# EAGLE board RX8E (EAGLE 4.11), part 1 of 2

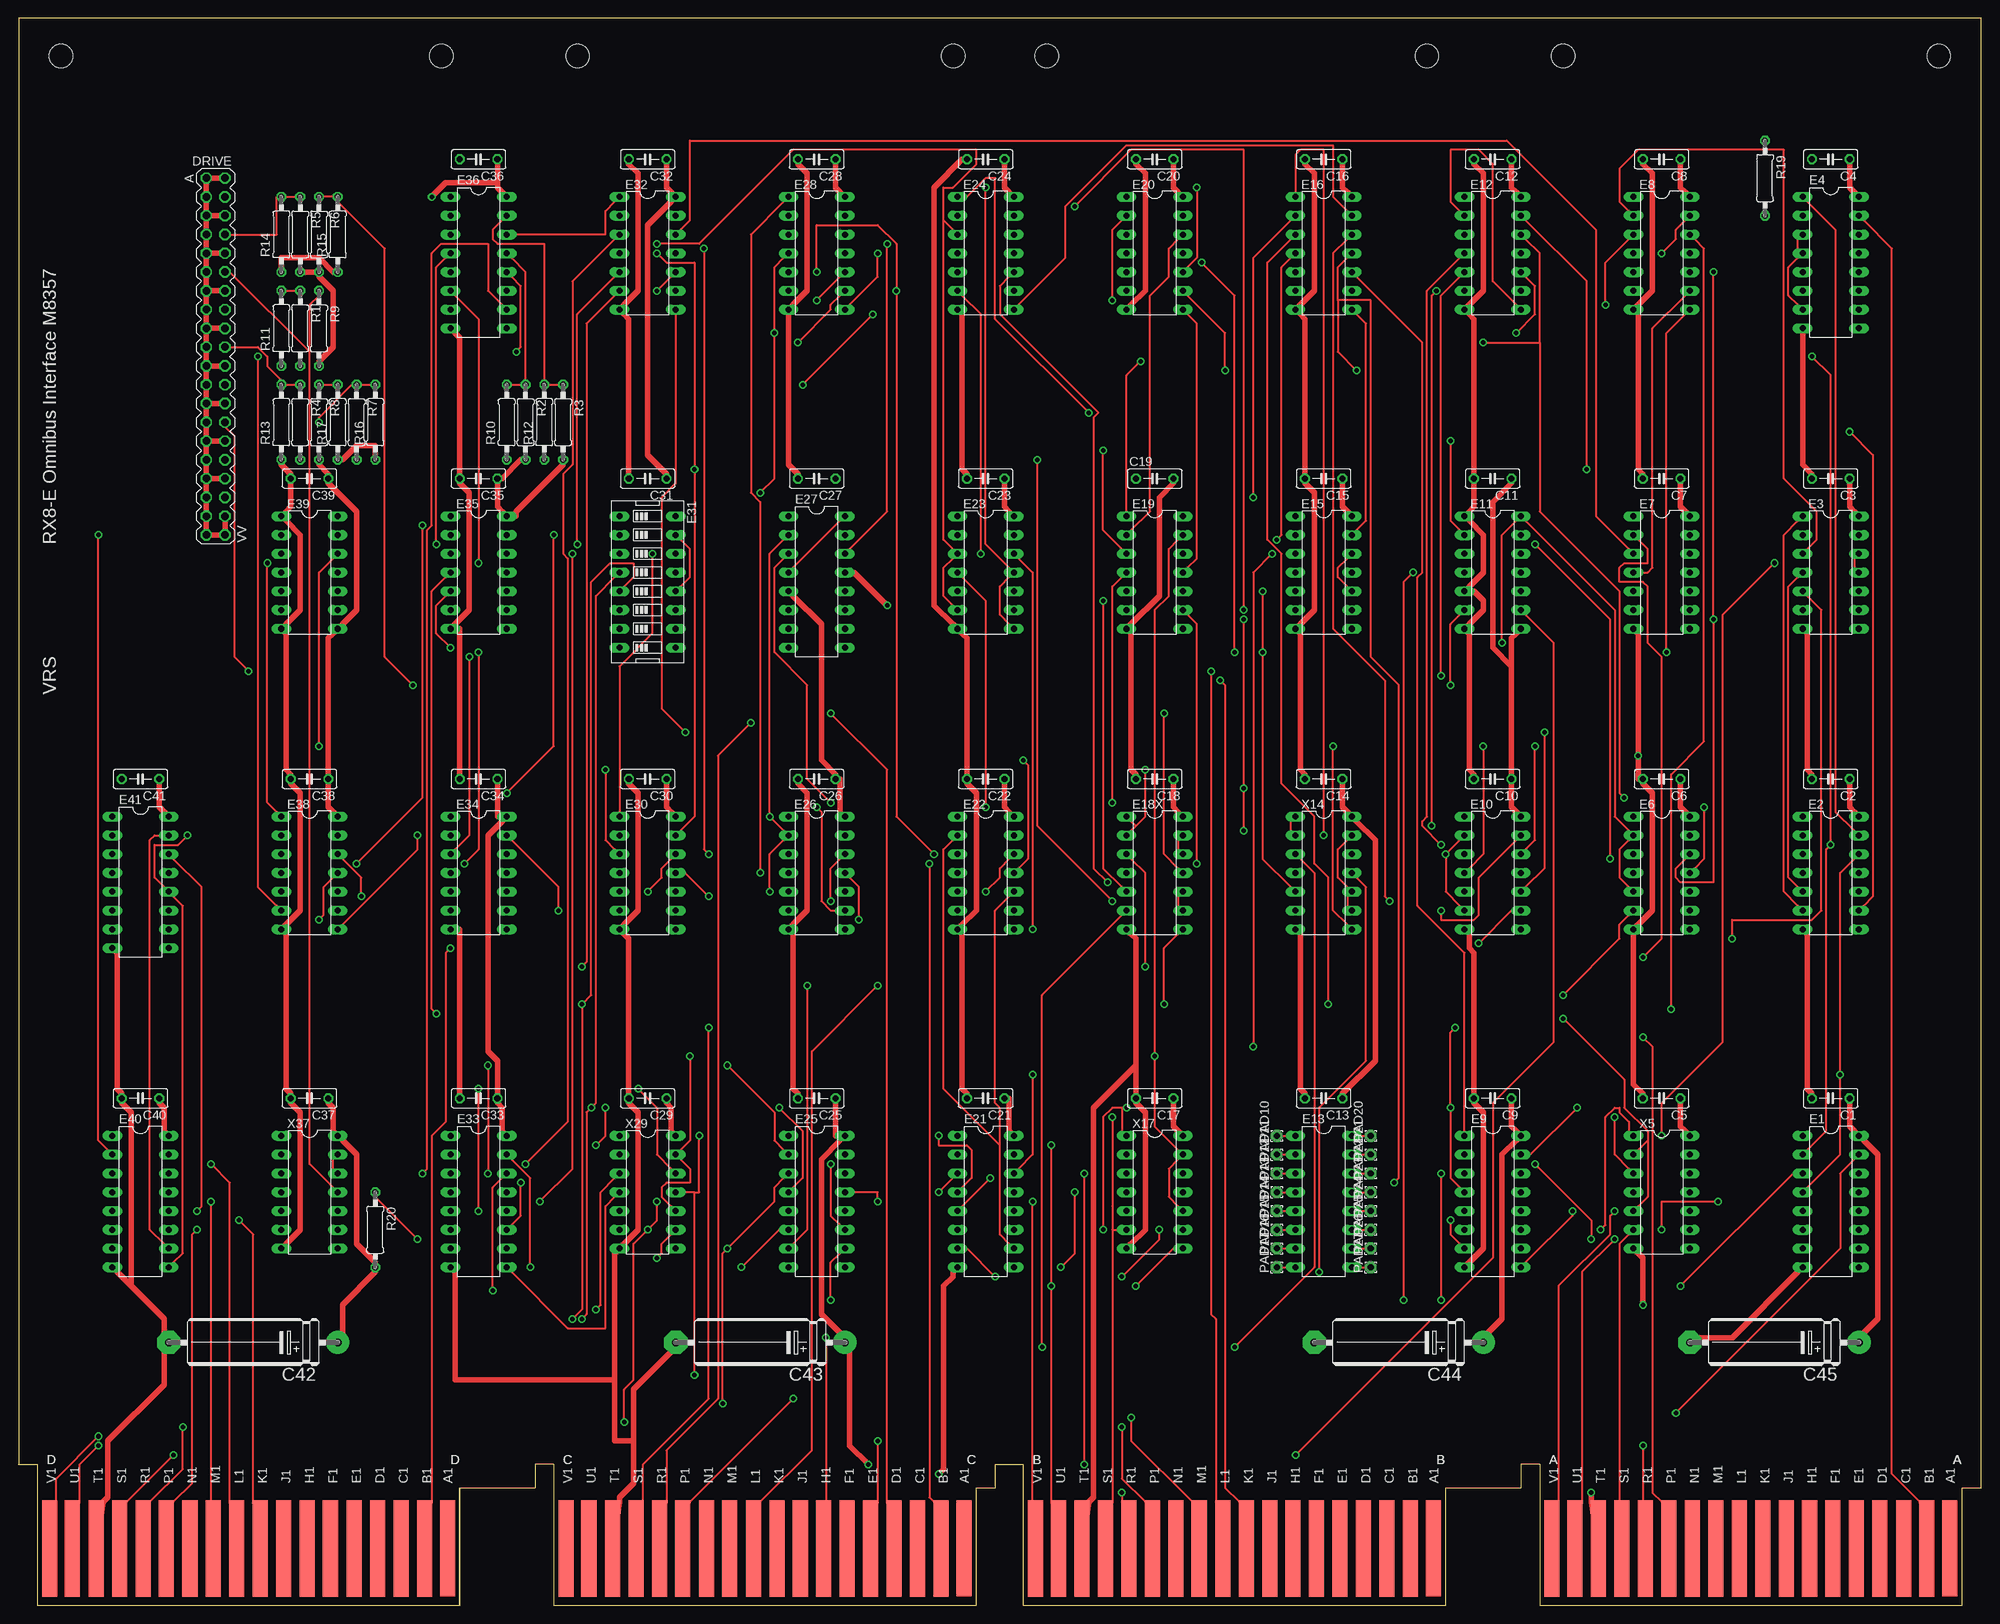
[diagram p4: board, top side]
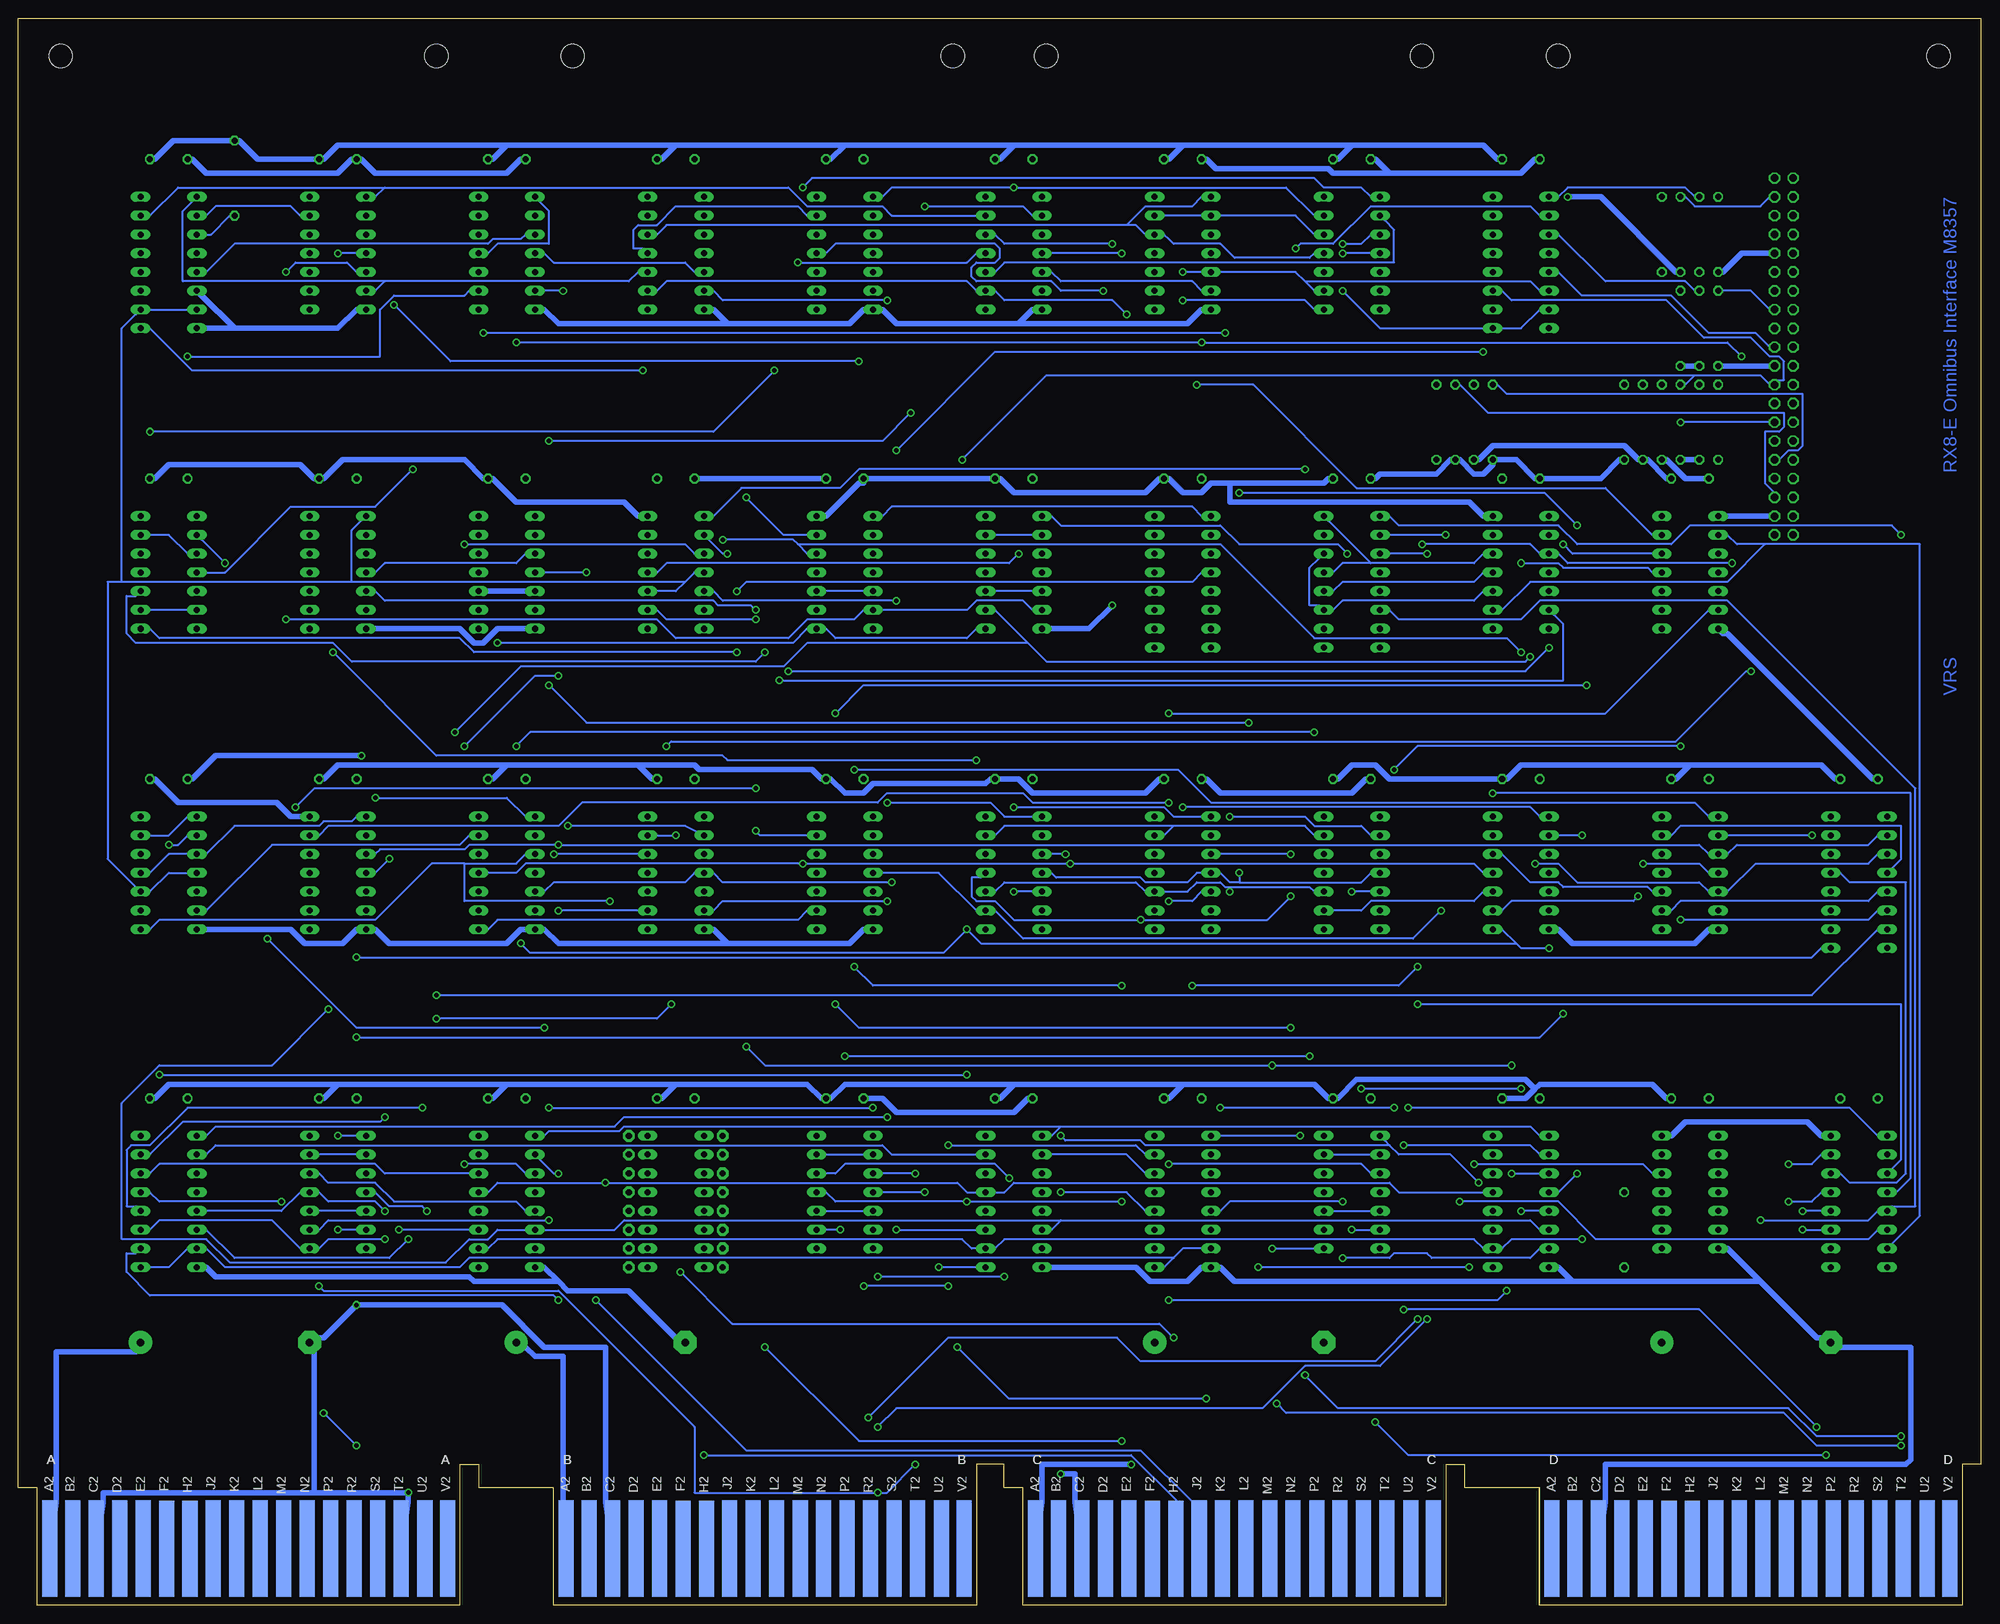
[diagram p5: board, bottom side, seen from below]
Size 265.43 x 214.63 mm. Coordinates in mm from the lower left corner, seen from the top.
Copper layers (1*16): Top 0.035mm / dielectric 1.5mm / Bottom 0.035mm
Design rules "olimex10mil": minimum track width 10mil, minimum drill 24mil, track to track 10mil, track to pad 10mil, pad to pad 10mil, via to via 10mil, smd to smd 10mil, copper to edge 25mil, drill to drill 10mil, minimum pad ring 10mil, minimum via ring 8mil, stop-mask expansion 0mil, vias tented up to drill 0mil, thermal gap 10mil
Net classes: 1 supply: width 0.762 mm

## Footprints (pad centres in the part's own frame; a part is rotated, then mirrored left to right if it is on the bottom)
C050-025X075 = drill 0.813 octagon: 1 -2.54,0; 2 2.54,0
E22-6 = drill 1.016 pad 3.15 round: + -11.43,0 | drill 1.016 pad 3.15 octagon: - 11.43,0
DEC40PIN = drill 1.016 octagon: A -24.13,-1.27; AA 3.81,-1.27; B -24.13,1.27; BB 3.81,1.27; C -21.59,-1.27; CC 6.35,-1.27; D -21.59,1.27; DD 6.35,1.27; E -19.05,-1.27; EE 8.89,-1.27; F -19.05,1.27; FF 8.89,1.27; H -16.51,-1.27; HH 11.43,-1.27; J -16.51,1.27; JJ 11.43,1.27; K -13.97,-1.27; KK 13.97,-1.27; L -13.97,1.27; LL 13.97,1.27; M -11.43,-1.27; MM 16.51,-1.27; N -11.43,1.27; NN 16.51,1.27; P -8.89,-1.27; PP 19.05,-1.27; R -8.89,1.27; RR 19.05,1.27; S -6.35,-1.27; SS 21.59,-1.27; T -6.35,1.27; TT 21.59,1.27; U -3.81,-1.27; UU 24.13,-1.27; V -3.81,1.27; VV 24.13,1.27; W -1.27,-1.27; X -1.27,1.27; Y 1.27,-1.27; Z 1.27,1.27
DIL16 = drill 0.813 long: 1 -8.89,-3.81; 2 -6.35,-3.81; 3 -3.81,-3.81; 4 -1.27,-3.81; 5 1.27,-3.81; 6 3.81,-3.81; 7 6.35,-3.81; 8 8.89,-3.81; 9 8.89,3.81; 10 6.35,3.81; 11 3.81,3.81; 12 1.27,3.81; 13 -1.27,3.81; 14 -3.81,3.81; 15 -6.35,3.81; 16 -8.89,3.81
DIL14 = drill 0.813 long: 1 -7.62,-3.81; 2 -5.08,-3.81; 3 -2.54,-3.81; 4 0,-3.81; 5 2.54,-3.81; 6 5.08,-3.81; 7 7.62,-3.81; 8 7.62,3.81; 9 5.08,3.81; 10 2.54,3.81; 11 0,3.81; 12 -2.54,3.81; 13 -5.08,3.81; 14 -7.62,3.81
EDG-08 = drill 0.813 long: 1 -8.89,-3.81; 2 -6.35,-3.81; 3 -3.81,-3.81; 4 -1.27,-3.81; 5 1.27,-3.81; 6 3.81,-3.81; 7 6.35,-3.81; 8 8.89,-3.81; 9 8.89,3.81; 10 6.35,3.81; 11 3.81,3.81; 12 1.27,3.81; 13 -1.27,3.81; 14 -3.81,3.81; 15 -6.35,3.81; 16 -8.89,3.81
1,6/0,8 = drill 0.813 pad 1.6 octagon: 1 0,0
0207/10 = drill 0.813 octagon: 1 -5.08,0; 2 5.08,0
EDGE-CON8 = smd 2.032 x 13.017: AA1 261.223,7.709; AB1 258.118,7.684; AC1 254.956,7.684; AD1 251.765,7.684; AE1 248.59,7.693; AF1 245.389,7.668; AH1 242.24,7.668; AJ1 239.09,7.668; AK1 235.915,7.668; AL1 232.74,7.693; AM1 229.54,7.693; AN1 226.39,7.693; AP1 223.19,7.668; AR1 220.04,7.668; AS1 216.865,7.693; AT1 213.69,7.693; AU1 210.49,7.693; AV1 207.404,7.668; BA1 191.373,7.709; BB1 188.268,7.684; BC1 185.106,7.684; BD1 181.915,7.684; BE1 178.74,7.693; BF1 175.539,7.668; BH1 172.39,7.668; BJ1 169.24,7.668; BK1 166.065,7.668; BL1 162.89,7.693; BM1 159.69,7.693; BN1 156.54,7.693; BP1 153.34,7.668; BR1 150.19,7.668; BS1 147.015,7.693; BT1 143.84,7.693; BU1 140.64,7.693; BV1 137.554,7.668; CA1 127.873,7.709; CB1 124.768,7.684; CC1 121.606,7.684; CD1 118.415,7.684; CE1 115.24,7.693; CF1 112.039,7.668; CH1 108.89,7.668; CJ1 105.74,7.668; CK1 102.565,7.668; CL1 99.39,7.693; CM1 96.19,7.693; CN1 93.04,7.693; CP1 89.84,7.668; CR1 86.69,7.668; CS1 83.515,7.693; CT1 80.34,7.693; CU1 77.14,7.693; CV1 74.054,7.668; DA1 58.023,7.709; DB1 54.918,7.684; DC1 51.756,7.684; DD1 48.565,7.684; DE1 45.39,7.693; DF1 42.189,7.668; DH1 39.04,7.668; DJ1 35.89,7.668; DK1 32.715,7.668; DL1 29.54,7.693; DM1 26.34,7.693; DN1 23.19,7.693; DP1 19.99,7.668; DR1 16.84,7.668; DS1 13.665,7.693; DT1 10.49,7.693; DU1 7.29,7.693; DV1 4.204,7.668 | smd 2.032 x 13.017 bottom: AA2 261.223,7.69; AB2 258.102,7.668; AC2 254.94,7.668; AD2 251.765,7.693; AE2 248.59,7.693; AF2 245.389,7.642; AH2 242.24,7.642; AJ2 239.09,7.668; AK2 235.915,7.668; AL2 232.74,7.693; AM2 229.54,7.693; AN2 226.39,7.693; AP2 223.19,7.668; AR2 220.04,7.668; AS2 216.865,7.693; AT2 213.69,7.693; AU2 210.464,7.693; AV2 207.404,7.668; BA2 191.373,7.69; BB2 188.252,7.668; BC2 185.09,7.668; BD2 181.915,7.693; BE2 178.74,7.693; BF2 175.539,7.642; BH2 172.39,7.642; BJ2 169.24,7.668; BK2 166.065,7.668; BL2 162.89,7.693; BM2 159.69,7.693; BN2 156.54,7.693; BP2 153.34,7.668; BR2 150.19,7.668; BS2 147.015,7.693; BT2 143.84,7.693; BU2 140.614,7.693; BV2 137.554,7.668; CA2 127.873,7.69; CB2 124.752,7.668; CC2 121.59,7.668; CD2 118.415,7.693; CE2 115.24,7.693; CF2 112.039,7.642; CH2 108.89,7.642; CJ2 105.74,7.668; CK2 102.565,7.668; CL2 99.39,7.693; CM2 96.19,7.693; CN2 93.04,7.693; CP2 89.84,7.668; CR2 86.69,7.668; CS2 83.515,7.693; CT2 80.34,7.693; CU2 77.114,7.693; CV2 74.054,7.668; DA2 58.023,7.69; DB2 54.902,7.668; DC2 51.74,7.668; DD2 48.565,7.693; DE2 45.39,7.693; DF2 42.189,7.642; DH2 39.04,7.642; DJ2 35.89,7.668; DK2 32.715,7.668; DL2 29.54,7.693; DM2 26.34,7.693; DN2 23.19,7.693; DP2 19.99,7.668; DR2 16.84,7.668; DS2 13.665,7.693; DT2 10.49,7.693; DU2 7.264,7.693; DV2 4.204,7.668
OMNIBUS = hole 3.175: 208.915,209.55; 259.715,209.55; 190.5,209.55; 139.065,209.55; 75.616,209.55; 126.416,209.55; 57.201,209.55; 5.766,209.55

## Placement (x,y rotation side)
C1  0.1  [C050-025X075]  245.11,68.58 180 top
C2  0.1  [C050-025X075]  245.11,111.76 180 top
C3  0.1  [C050-025X075]  245.11,152.4 180 top
C4  0.1  [C050-025X075]  245.11,195.58 180 top
C5  0.1  [C050-025X075]  222.25,68.58 180 top
C6  0.1  [C050-025X075]  222.25,111.76 180 top
C7  0.1  [C050-025X075]  222.25,152.4 180 top
C8  0.1  [C050-025X075]  222.25,195.58 180 top
C9  0.1  [C050-025X075]  199.39,68.58 180 top
C10  0.1  [C050-025X075]  199.39,111.76 180 top
C11  0.1  [C050-025X075]  199.39,152.4 180 top
C12  0.1  [C050-025X075]  199.39,195.58 180 top
C13  0.1  [C050-025X075]  176.53,68.58 180 top
C14  0.1  [C050-025X075]  176.53,111.76 180 top
C15  0.1  [C050-025X075]  176.53,152.4 180 top
C16  0.1  [C050-025X075]  176.53,195.58 180 top
C17  0.1  [C050-025X075]  153.67,68.58 180 top
C18  0.1  [C050-025X075]  153.67,111.76 180 top
C19  0.1  [C050-025X075]  153.67,152.4 0 top
C20  0.1  [C050-025X075]  153.67,195.58 180 top
C21  0.1  [C050-025X075]  130.81,68.58 180 top
C22  0.1  [C050-025X075]  130.81,111.76 180 top
C23  0.1  [C050-025X075]  130.81,152.4 180 top
C24  0.1  [C050-025X075]  130.81,195.58 180 top
C25  0.1  [C050-025X075]  107.95,68.58 180 top
C26  0.1  [C050-025X075]  107.95,111.76 180 top
C27  0.1  [C050-025X075]  107.95,152.4 180 top
C28  0.1  [C050-025X075]  107.95,195.58 180 top
C29  0.1  [C050-025X075]  85.09,68.58 180 top
C30  0.1  [C050-025X075]  85.09,111.76 180 top
C31  0.1  [C050-025X075]  85.09,152.4 180 top
C32  0.1  [C050-025X075]  85.09,195.58 180 top
C33  0.1  [C050-025X075]  62.23,68.58 180 top
C34  0.1  [C050-025X075]  62.23,111.76 180 top
C35  0.1  [C050-025X075]  62.23,152.4 180 top
C36  0.1  [C050-025X075]  62.23,195.58 180 top
C37  0.1  [C050-025X075]  39.37,68.58 180 top
C38  0.1  [C050-025X075]  39.37,111.76 180 top
C39  0.1  [C050-025X075]  39.37,152.4 180 top
C40  0.1  [C050-025X075]  16.51,68.58 180 top
C41  0.1  [C050-025X075]  16.51,111.76 180 top
C42  6.8uf  [E22-6]  31.75,35.56 180 top
C43  6.8uf  [E22-6]  100.33,35.56 180 top
C44  6.8uf  [E22-6]  186.69,35.56 180 top
C45  6.8uf  [E22-6]  237.49,35.56 180 top
DRIVE  [DEC40PIN]  26.67,168.91 270 top
E1  DS8837N  [DIL16]  245.11,54.61 270 top
E2  74LS74N  [DIL14]  245.11,99.06 270 top
E3  74LS10N  [DIL14]  245.11,139.7 270 top
E4  74161N  [DIL16]  245.11,181.61 270 top
E6  74LS02N  [DIL14]  222.25,99.06 270 top
E7  74LS74N  [DIL14]  222.25,139.7 270 top
E8  74LS04N  [DIL14]  222.25,182.88 270 top
E9  74179N  [DIL16]  199.39,54.61 270 top
E10  74LS10N  [DIL14]  199.39,99.06 270 top
E11  DS8640N  [DIL14]  199.39,139.7 270 top
E12  74LS00N  [DIL14]  199.39,182.88 270 top
E13  SPARE  [DIL16]  176.53,54.61 270 top
E15  74LS74N  [DIL14]  176.53,139.7 270 top
E16  74LS08N  [DIL14]  176.53,182.88 270 top
E18X  7438N  [DIL14]  153.67,99.06 270 top
E19  74LS02N  [DIL14]  153.67,139.7 270 top
E20  74LS27N  [DIL14]  153.67,182.88 270 top
E21  74179N  [DIL16]  130.81,54.61 270 top
E22  74LS74N  [DIL14]  130.81,99.06 270 top
E23  74LS02N  [DIL14]  130.81,139.7 270 top
E24  74LS00N  [DIL14]  130.81,182.88 270 top
E25  DS8837N  [DIL16]  107.95,54.61 270 top
E26  74LS74N  [DIL14]  107.95,99.06 270 top
E27  7476N  [DIL16]  107.95,138.43 270 top
E28  74LS20N  [DIL14]  107.95,182.88 270 top
E30  74LS74N  [DIL14]  85.09,99.06 270 top
E31  [EDG-08]  85.09,138.43 270 top
E32  74LS04N  [DIL14]  85.09,182.88 270 top
E33  74179N  [DIL16]  62.23,54.61 270 top
E34  7400N  [DIL14]  62.23,99.06 270 top
E35  SP314N  [DIL14]  62.23,139.7 270 top
E36  DS8837N  [DIL16]  62.23,181.61 270 top
E38  74LS04N  [DIL14]  39.37,99.06 270 top
E39  SP384N  [DIL14]  39.37,139.7 270 top
E40  DS8837N  [DIL16]  16.51,54.61 270 top
E41  74LS42N  [DIL16]  16.51,97.79 270 top
PAD10  [1,6/0,8]  170.18,63.5 90 top
PAD11  [1,6/0,8]  170.18,60.96 90 top
PAD12  [1,6/0,8]  170.18,58.42 90 top
PAD13  [1,6/0,8]  170.18,55.88 90 top
PAD14  [1,6/0,8]  170.18,53.34 90 top
PAD15  [1,6/0,8]  170.18,50.8 90 top
PAD16  [1,6/0,8]  170.18,48.26 90 top
PAD17  [1,6/0,8]  170.18,45.72 90 top
PAD20  [1,6/0,8]  182.88,63.5 90 top
PAD21  [1,6/0,8]  182.88,60.96 90 top
PAD22  [1,6/0,8]  182.88,58.42 90 top
PAD23  [1,6/0,8]  182.88,55.88 90 top
PAD24  [1,6/0,8]  182.88,53.34 90 top
PAD25  [1,6/0,8]  182.88,50.8 90 top
PAD26  [1,6/0,8]  182.88,48.26 90 top
PAD27  [1,6/0,8]  182.88,45.72 90 top
R1  180  [0207/10]  38.1,172.72 270 top
R2  180  [0207/10]  68.58,160.02 270 top
R3  180  [0207/10]  73.66,160.02 270 top
R4  180  [0207/10]  38.1,160.02 270 top
R5  180  [0207/10]  38.1,185.42 270 top
R6  180  [0207/10]  40.64,185.42 270 top
R7  180  [0207/10]  45.72,160.02 270 top
R8  180  [0207/10]  40.64,160.02 270 top
R9  120  [0207/10]  40.64,172.72 270 top
R10  390  [0207/10]  66.04,160.02 90 top
R11  390  [0207/10]  35.56,172.72 90 top
R12  390  [0207/10]  71.12,160.02 90 top
R13  390  [0207/10]  35.56,160.02 90 top
R14  390  [0207/10]  35.56,185.42 90 top
R15  390  [0207/10]  43.18,185.42 90 top
R16  390  [0207/10]  48.26,160.02 90 top
R17  390  [0207/10]  43.18,160.02 90 top
R19  10K  [0207/10]  236.22,193.04 270 top
R20  10K  [0207/10]  48.26,50.8 270 top
U$2  [EDGE-CON8]  0,0 0 top
U$5  OUTLINE-OMNIBUS  [OMNIBUS]  0,0 0 top
X5  7438N  [DIL14]  222.25,55.88 270 top
X14  7438N  [DIL14]  176.53,99.06 270 top
X17  7438N  [DIL14]  153.67,55.88 270 top
X29  7438N  [DIL14]  85.09,55.88 270 top
X37  7438N  [DIL14]  39.37,55.88 270 top

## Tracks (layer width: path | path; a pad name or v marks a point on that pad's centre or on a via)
8/12  (via drill 0.61)
  Top 0.254: E2.5 240.66,97.16 239.4,98.43 239.4,137.8 240.66,139.07 E3.4 | v212.09,153.67 212.09,179.07 203.84,187.33 E12.13
  Bottom 0.254: v212.09,153.67 217.17,148.59 228.6,148.59 237.49,139.7 240.03,139.7 E3.4
8/12\  (via drill 0.61)
  Top 0.254: E3.1 240.66,146.69 238.76,144.78 238.76,96.52 240.66,94.62 E2.6 | X14.9 179.71,94.62 179.71,95.89 X14.10 179.71,97.16 178.44,98.43 178.44,102.24 179.71,103.51 X14.13 | v176.53,104.14 176.53,196.85 173.35,196.85 172.72,196.22 172.72,191.14 E16.1 | v192.41,93.98 192.41,92.71 196.85,92.71 197.49,93.35 197.49,98.43 202.56,103.51 E10.13
  Bottom 0.254: E2.6 240.03,93.98 231.14,102.87 205.74,102.87 204.47,104.14 E10.13 | v176.53,104.14 179.07,104.14 X14.13 | v192.41,93.98 181.61,93.98 X14.9
A-
  Top 0.254: E4.3 240.66,184.79 240.66,183.52 E4.4 240.66,182.25 239.4,180.98 239.4,177.17 240.66,175.9 E4.7 | E15.12 179.71,141.61 178.44,140.34 178.44,139.07 179.71,137.8 E15.10
  Bottom 0.254: E4.7 242.57,175.26 247.65,175.26 E4.10 249.56,174.63 251.46,172.72 251.46,138.43 | R19.2 236.85,187.96 239.4,185.42 240.03,185.42 E4.3 | E2.4 242.57,99.06 245.11,99.06 247.65,96.52 E2.10 249.56,97.16 253.37,100.97 253.37,138.43 251.46,138.43 | 175.26,138.43 176.53,137.16 179.07,137.16 E15.10 | 175.26,138.43 173.99,139.7 E15.4 | 220.34,138.43 220.34,145.42 219.07,146.69 E7.1 | 175.26,138.43 220.34,138.43 | 220.34,138.43 251.46,138.43
B-  (via drill 0.61)
  Top 0.254: E27.2 103.5,144.15 101.6,142.24 v101.6,106.68 103.5,104.78 E26.2 103.5,103.51 101.6,101.6 v101.6,96.52 | v53.98,49.53 48.26,55.25 R20.1 | 132.72,62.23 132.72,67.31 132.08,67.95 132.08,93.98 133.99,95.89 E22.10 | 132.72,62.23 132.72,50.17 133.99,48.9 E21.10 | 132.72,62.23 125.09,69.85 125.09,102.24 126.36,103.51 E22.2
  Bottom 0.254: v101.6,106.68 91.44,106.68 90.17,105.41 83.82,105.41 82.55,104.14 E30.2 | v53.98,49.53 63.5,49.53 64.77,48.26 E33.10 67.31,48.26 68.58,49.53 132.08,49.53 133.35,48.26 E21.10 135.89,48.26 136.53,48.26 137.79,49.53 200.66,49.53 201.93,48.26 E9.10 | 101.6,97.16 102.23,97.16 102.87,97.79 106.05,97.79 107.31,96.52 110.49,96.52 E26.10 113.03,96.52 114.3,97.79 132.08,97.79 133.35,96.52 E22.10 | 101.6,97.16 90.81,97.16 90.17,96.52 E30.10 | 101.6,97.16 v101.6,96.52
B_MAINT  (via drill 0.61)
  Top 0.254: v86.36,177.8 88.27,179.71 E32.10
  Bottom 0.254: E36.7 59.69,175.26 62.23,172.72 64.77,172.72 E36.9 67.31,172.72 81.28,172.72 v86.36,177.8
BINIT\  (via drill 0.61)
  Top 0.254: v86.36,182.88 87.63,181.61 91.44,181.61 v91.44,153.67 91.44,106.68 89.53,104.78 E30.13
  Bottom 0.254: 109.22,105.41 91.44,105.41 90.17,104.14 E30.13 | 109.22,105.41 110.49,104.14 E26.13 | 109.22,105.41 132.08,105.41 133.35,104.14 E22.13 | v86.36,182.88 82.55,182.88 E32.4 | v91.44,153.67 151.76,153.67 154.31,151.13 167.64,151.13 171.45,147.32 E15.1
BTP3
  Top 0.254: E7.3 217.81,142.88 213.36,147.32 213.36,186.06 201.29,198.12 90.81,198.12 90.81,187.33 89.53,186.06 E32.12
  Bottom 0.254: E32.12 90.17,185.42 92.71,187.96 102.87,187.96 E28.2 105.41,187.96 110.49,187.96 E28.13
BTP4  (via drill 0.61)
  Top 0.254: v93.34,95.89 90.17,99.06 E30.11 | v113.67,92.71 113.67,97.16 112.39,98.43 E26.11 | v222.88,128.91 222.88,172.09 225.43,174.63 E8.8 | v135.89,114.3 136.53,113.67 136.53,100.97 135.25,99.7 E22.11
  Bottom 0.254: v93.34,95.89 96.52,92.71 v113.67,92.71 130.81,92.71 133.35,95.25 135.89,95.25 136.53,95.89 136.53,98.43 135.25,98.43 E22.11 | v222.88,128.91 208.91,114.94 170.18,114.94 169.54,114.3 v135.89,114.3
C0\  (via drill 0.61)
  Top 0.254: v164.47,34.93 175.26,45.72 175.26,99.06 173.35,100.97 X14.3 | v116.2,22.23 116.2,13.97 U$2.CE1
  Bottom 0.254: v164.47,34.93 151.76,22.23 v116.2,22.23
C1\  (via drill 0.61)
  Top 0.254: v175.9,45.09 175.9,67.31 182.25,73.66 182.25,97.16 180.97,98.43 X14.11 | v109.22,36.2 109.22,13.97 U$2.CH1
  Bottom 0.254: v175.9,45.09 168.91,38.1 111.12,38.1 v109.22,36.2
CLK_BUF\  (via drill 0.61)
  Top 0.254: v223.52,80.65 223.52,112.4 227.97,116.84 227.97,183.52 226.69,184.79 E8.12
  Bottom 0.254: 124.46,52.07 60.96,52.07 59.69,50.8 E33.6 | 124.46,52.07 125.73,50.8 E21.6 | 124.46,52.07 183.51,52.07 184.78,50.8 194.31,50.8 E9.6 196.85,50.8 200.66,50.8 201.93,49.53 204.47,49.53 207.65,46.36 236.85,46.36 240.03,49.53 251.46,49.53 251.46,67.95 246.38,73.03 231.14,73.03 v223.52,80.65
CLK_PARITY\  (via drill 0.61)
  Top 0.254: v214.63,175.9 214.63,181.61 217.81,184.79 E8.3 | v151.76,168.28 149.86,166.37 149.86,147.96 E19.1
  Bottom 0.254: E27.1 105.41,147.32 106.68,148.59 147.32,148.59 148.59,147.32 E19.1 | v214.63,175.9 207.01,168.28 v151.76,168.28
DATA0
  Bottom 0.254: E9.14 204.47,58.42 215.9,58.42 217.17,59.69 246.38,59.69 247.65,58.42 E1.14
DATA0\  (via drill 0.61)
  Top 0.254: v215.9,66.04 215.9,60.96 217.81,59.06 X5.3 | v219.71,21.59 219.71,13.97 U$2.AR1 | v224.16,26.04 246.38,48.26 246.38,58.42 248.28,60.33 E1.15
  Bottom 0.254: v215.9,66.04 216.53,65.41 243.21,65.41 247.65,60.96 E1.15 | v224.16,26.04 v219.71,21.59
DATA1  (via drill 0.61)
  Top 0.254: v210.82,67.31 204.47,60.96 E9.15
  Bottom 0.254: v210.82,67.31 242.57,67.31 247.65,62.23 250.19,62.23 250.82,61.6 250.82,53.98 249.56,53.98 E1.12
DATA1\  (via drill 0.61)
  Top 0.254: X5.6 217.81,50.17 216.53,48.9 216.53,13.97 U$2.AS1 | v229.87,54.61 222.25,54.61 v222.25,50.8
  Bottom 0.254: v229.87,54.61 246.38,54.61 247.65,55.88 E1.13 | v222.25,50.8 219.71,50.8 X5.6
DATA2  (via drill 0.61)
  Top 0.254: v192.41,58.42 v192.41,41.28
  Bottom 0.254: v192.41,58.42 193.04,58.42 194.94,60.33 E9.2 | v192.41,41.28 193.04,41.91 247.65,41.91 250.82,45.09 250.82,47.63 249.56,47.63 E1.10
DATA2\  (via drill 0.61)
  Top 0.254: v215.9,49.53 211.46,45.09 211.46,13.97 U$2.AU1
  Bottom 0.254: E1.11 247.65,50.8 246.38,52.07 231.14,52.07 227.33,48.26 X5.8 224.79,48.26 223.52,49.53 v215.9,49.53
DATA3  (via drill 0.61)
  Top 0.254: v205.1,59.69 212.72,52.07 v212.72,49.53
  Bottom 0.254: v205.1,59.69 198.12,59.69 196.85,58.42 E9.3 | v212.72,49.53 215.26,46.99 236.22,46.99 240.03,50.8 E1.6
DATA3\  (via drill 0.61)
  Top 0.254: v215.9,53.34 215.26,52.71 215.26,50.17 208.28,43.18 208.28,13.97 U$2.AV1
  Bottom 0.254: E1.5 240.03,53.34 229.87,53.34 227.33,55.88 X5.11 224.79,55.88 223.52,54.61 217.17,54.61 v215.9,53.34
DATA4  (via drill 0.61)
  Top 0.254: E1.4 241.94,56.52 246.38,60.96 v246.38,71.76 246.38,99.06 248.28,100.97 E2.12 | v137.16,71.76 137.16,60.96 135.25,59.06 E21.14
  Bottom 0.254: v246.38,71.76 v137.16,71.76
DATA4\  (via drill 0.61)
  Top 0.254: v144.15,19.05 v144.15,58.42 | v149.22,15.24 149.22,13.97 U$2.BR1 | v224.79,43.18 240.03,58.42 E1.3
  Bottom 0.254: v144.15,58.42 148.59,58.42 X17.3 | v144.15,19.05 147.96,15.24 v149.22,15.24 173.99,15.24 173.99,24.13 192.41,42.55 224.16,42.55 v224.79,43.18
DATA5  (via drill 0.61)
  Top 0.254: E1.2 241.94,61.6 244.47,64.14 244.47,102.24 v245.11,102.87 245.11,166.37 v242.57,168.91
  Bottom 0.254: E21.15 135.89,60.96 147.32,60.96 148.59,62.23 238.76,62.23 240.03,60.96 E1.2 | v245.11,102.87 243.84,102.87 242.57,104.14 E2.2 | v242.57,168.91 216.53,168.91 216.53,175.26 214.63,177.17 205.1,177.17 204.47,177.8 E12.9
DATA5\  (via drill 0.61)
  Top 0.254: 147.96,50.8 147.96,53.98 v147.96,66.04 | 147.96,50.8 147.96,13.97 U$2.BS1 | 147.96,50.8 148.59,50.8 X17.6
  Bottom 0.254: v147.96,66.04 183.51,66.04 184.78,64.77 238.76,64.77 240.03,63.5 E1.1
DATA6
  Bottom 0.254: E25.14 113.03,58.42 115.57,60.96 125.73,60.96 E21.2
DATA6\  (via drill 0.61)
  Top 0.254: v139.7,62.23 v139.7,43.18 139.7,13.97 U$2.BU1 | v151.13,43.18 156.21,48.26 X17.8
  Bottom 0.254: v139.7,62.23 114.3,62.23 113.03,60.96 E25.15 | v139.7,43.18 v151.13,43.18
DATA7  (via drill 0.61)
  Top 0.254: v124.46,55.88 126.36,57.79 E21.3
  Bottom 0.254: v124.46,55.88 115.57,55.88 113.03,53.34 E25.12
DATA7\  (via drill 0.61)
  Top 0.254: v116.2,54.61 116.2,55.88 113.03,55.88 E25.13 | v137.16,54.61 137.16,13.97 U$2.BV1
  Bottom 0.254: v116.2,54.61 v137.16,54.61 154.94,54.61 156.21,55.88 X17.11
DATA8  (via drill 0.61)
  Top 0.254: v64.14,42.55 64.14,56.52 65.41,57.79 E33.14 | v109.86,41.28 109.86,46.36 111.12,47.63 E25.10
  Bottom 0.254: v64.14,42.55 65.41,41.28 v109.86,41.28
DATA8\  (via drill 0.61)
  Top 0.254: v109.86,59.69 109.86,52.71 111.12,51.44 E25.11 | v22.23,24.13 22.23,18.42 17.78,13.97 U$2.DR1 | v78.11,40.01 78.74,40.64 78.74,55.88 80.64,57.79 X29.3
  Bottom 0.254: v109.86,59.69 83.82,59.69 82.55,58.42 X29.3 | v22.23,24.13 38.1,40.01 v78.11,40.01
DATA9  (via drill 0.61)
  Top 0.254: v69.22,45.72 69.22,57.79 66.67,60.33 E33.15 | v97.79,45.72 102.87,50.8 E25.6
  Bottom 0.254: v69.22,45.72 v97.79,45.72
DATA9\  (via drill 0.61)
  Top 0.254: v86.36,54.61 86.36,52.07 v85.09,50.8 83.19,48.9 83.19,30.48 81.92,29.21 v81.92,24.77 | v20.95,20.32 14.61,13.97 U$2.DS1
  Bottom 0.254: v85.09,50.8 82.55,50.8 X29.6 | v86.36,54.61 101.6,54.61 102.87,53.34 E25.5 | v81.92,24.77 77.47,20.32 v20.95,20.32
DATA10  (via drill 0.61)
  Top 0.254: v78.11,62.23 79.38,63.5 v79.38,67.31 | v102.87,67.31 106.05,64.14 106.05,57.79 104.78,56.52 E25.4
  Bottom 0.254: v78.11,62.23 60.96,62.23 59.69,60.96 E33.2 | v79.38,67.31 v102.87,67.31
DATA10\  (via drill 0.61)
  Top 0.254: E25.3 103.5,57.79 102.23,56.52 102.23,54.61 v95.89,48.26 95.25,47.63 v95.25,27.31 | v10.79,21.59 8.26,19.05 8.26,13.97 U$2.DU1
  Bottom 0.254: v95.89,48.26 90.17,48.26 X29.8 | v95.25,27.31 93.98,26.04 26.67,26.04 22.23,21.59 v10.79,21.59
DATA11  (via drill 0.61)
  Top 0.254: v63.5,73.03 v63.5,58.42 | v95.89,73.03 102.23,66.68 102.23,62.87 103.5,61.6 E25.2 | v169.54,142.24 167,139.7 v167,75.57
  Bottom 0.254: v63.5,58.42 59.69,58.42 E33.3 | v63.5,73.03 v95.89,73.03 164.47,73.03 v167,75.57 | v169.54,142.24 170.18,142.24 172.09,144.15 E15.2
DATA11\  (via drill 0.61)
  Top 0.254: 91.44,55.88 92.08,55.88 v92.08,63.5 | 91.44,55.88 90.17,55.88 X29.11 | v91.44,31.12 91.44,55.88 | v10.79,22.86 5.08,17.15 5.08,13.97 U$2.DV1
  Bottom 0.254: v92.08,63.5 102.87,63.5 E25.1 | v91.44,31.12 87,26.67 26.04,26.67 22.23,22.86 v10.79,22.86
DONE  (via drill 0.61)
  Top 0.254: v62.23,140.97 62.23,173.99 59.05,177.17 E36.6 | v123.83,101.6 118.75,106.68 v118.75,177.8 118.75,184.15 116.2,186.69 107.95,186.69 v107.95,180.34
  Bottom 0.254: v62.23,140.97 57.15,140.97 56.52,140.34 45.09,140.34 44.45,139.7 E39.11 | 91.44,179.07 92.71,180.34 102.87,180.34 E28.5 105.41,180.34 v107.95,180.34 | 91.44,179.07 90.17,177.8 E32.9 | 91.44,179.07 60.96,179.07 59.69,177.8 E36.6 | v123.83,101.6 125.73,101.6 E22.3 | v118.75,177.8 124.46,177.8 125.73,179.07 135.89,179.07 136.53,179.71 136.53,180.98 135.89,181.61 133.35,181.61 132.72,182.25 132.72,183.52 133.35,184.15 154.94,184.15 156.21,182.88 E20.11
DONE\  (via drill 0.61)
  Top 0.254: v107.95,176.53 111.12,179.71 E28.10 | v198.12,116.21 198.12,101.6 196.22,99.7 E10.4 | v90.17,118.11 87,121.29 87,149.86 88.9,151.77 88.9,174.63 E32.8
  Bottom 0.254: v107.95,176.53 91.44,176.53 90.17,175.26 E32.8 | v198.12,116.21 196.22,118.11 v90.17,118.11
DONE_SKIP\  (via drill 0.61)
  Top 0.254: v159.38,100.33 159.38,132.72 158.12,133.99 E19.9 | v123.19,100.33 123.19,14.61 123.83,13.97 U$2.CB1
  Bottom 0.254: E34.11 67.31,99.06 68.58,100.33 v123.19,100.33 v159.38,100.33 196.85,100.33 198.12,99.06 201.93,99.06 E10.11
ENB_BUF_LD\  (via drill 0.61)
  Top 0.254: v180.97,167.01 178.44,169.55 178.44,176.53 | 178.44,176.53 178.44,180.98 179.71,182.25 E16.11 | 178.44,176.53 182.88,176.53 182.88,128.27 186.69,124.46 186.69,57.79 v186.06,57.15
  Bottom 0.254: E20.13 158.75,187.96 160.02,189.23 176.53,189.23 179.07,186.69 181.61,186.69 182.25,186.06 182.25,183.52 180.97,183.52 E16.11 | v180.97,167.01 241.94,167.01 247.65,172.72 E4.9 | E33.13 67.31,55.88 78.74,55.88 80.01,57.15 130.81,57.15 132.08,55.88 133.35,55.88 E21.13 135.89,55.88 137.16,55.88 138.43,57.15 v186.06,57.15 200.66,57.15 201.93,55.88 E9.13
ERR_SKIP\  (via drill 0.61)
  Top 0.254: v60.96,128.27 60.96,104.14 59.05,102.24 E34.3 | v206.38,118.11 206.38,99.7 203.84,97.16 E10.10
  Bottom 0.254: v60.96,128.27 61.59,127.64 126.36,127.64 128.91,130.18 | 128.91,130.18 133.35,134.62 E23.9 | v206.38,118.11 197.49,127 161.93,127 158.75,130.18 128.91,130.18
ERROR  (via drill 0.61)
  Top 0.254: v93.34,101.6 92.71,102.24 v92.71,183.52
  Bottom 0.254: v93.34,101.6 102.87,101.6 E26.3 | v92.71,183.52 92.08,184.15 87.63,184.15 82.55,189.23 60.96,189.23 59.69,187.96 E36.2
GND  (via drill 0.61)
  Top 0.762: C21.2 128.27,69.22 127.64,69.85 127.64,90.81 E22.7 127.64,92.08 129.54,93.98 129.54,109.86 128.27,111.13 C22.2 128.27,112.4 128.27,130.81 127.64,131.45 E23.7 126.36,132.72 123.83,135.26 123.83,191.77 127.64,195.58 C24.2 | v117.47,135.26 113.03,139.7 E27.13 | v212.72,15.24 212.72,13.97 U$2.AT2 | v219.71,40.64 219.71,46.99 219.07,47.63 X5.7 | E1.8 240.66,45.09 231.78,36.2 227.33,36.2 C45.- | C1.2 242.57,69.22 241.94,69.85 241.94,90.81 E2.7 | C2.2 242.57,112.4 241.94,113.03 241.94,131.45 E3.7 | C5.2 219.71,69.22 218.44,70.49 218.44,90.81 E6.7 219.07,92.08 220.98,93.98 220.98,109.86 219.71,111.13 C6.2 219.07,111.76 v219.07,114.94 219.07,131.45 E7.7 | E10.7 196.22,90.81 196.22,88.9 196.85,88.27 196.85,69.22 C9.2 196.85,67.95 198.12,66.68 198.12,48.26 196.22,46.36 E9.8 | C13.2 173.99,69.22 173.35,69.85 173.35,90.81 X14.7 | X17.7 150.5,48.9 152.4,50.8 152.4,66.68 151.13,67.95 C17.2 151.13,69.22 151.13,73.03 | 151.13,73.03 151.13,90.17 150.5,90.81 E18X.7 | 151.13,73.03 145.41,67.31 145.41,14.61 144.78,13.97 U$2.BT1 | C7.2 219.71,153.04 219.07,153.67 219.07,174.63 E8.7 219.07,175.9 220.98,177.8 220.98,193.68 219.71,194.95 C8.2 | C3.2 242.57,153.04 241.3,154.31 241.3,172.09 E4.8 | C10.2 196.85,112.4 196.22,113.03 196.22,131.45 E11.7 196.22,132.72 198.12,134.62 198.12,135.89 196.85,137.16 E11.5 196.22,137.8 198.12,139.7 198.12,144.78 196.22,146.69 E11.1 196.22,147.96 196.85,148.59 196.85,151.77 C11.2 196.85,153.04 196.85,173.99 196.22,174.63 E12.7 196.22,175.9 198.12,177.8 198.12,193.68 196.85,194.95 C12.2 | C27.2 105.41,153.04 104.14,154.31 104.14,174.63 E28.7 104.78,175.9 106.68,177.8 106.68,193.68 105.41,194.95 C28.2
  Top 0.762: E20.7 150.5,175.9 152.4,177.8 152.4,193.68 151.13,194.95 C20.2 | C23.2 128.27,153.04 127.64,153.67 127.64,174.63 E24.7 | C14.2 173.99,112.4 173.35,113.03 173.35,131.45 E15.7 173.35,132.72 175.26,134.62 175.26,150.5 173.99,151.77 C15.2 173.99,153.04 173.99,173.99 173.35,174.63 E16.7 173.35,175.9 175.26,177.8 175.26,193.68 173.99,194.95 C16.2 | C18.2 151.13,112.4 150.5,113.03 150.5,131.45 E19.7 150.5,132.72 154.31,136.53 154.31,149.86 156.21,151.77 C19.2 | C33.2 59.69,69.22 59.69,91.44 E34.7 | R15.1 42.55,180.34 40.64,182.25 35.56,182.25 35.56,180.98 R14.1 | R13.1 35.56,154.31 36.83,153.04 C39.2 36.83,151.77 36.83,148.59 36.2,147.96 E39.1 36.2,146.69 38.1,144.78 38.1,134.62 36.2,132.72 E39.7 36.2,131.45 36.2,113.03 36.83,112.4 C38.2 36.83,111.13 38.1,109.86 38.1,93.98 36.2,92.08 E38.7 36.2,90.81 36.2,69.85 36.83,69.22 C37.2 36.83,67.95 38.1,66.68 38.1,50.8 36.2,48.9 X37.7 | DRIVE.MM 25.4,151.77 25.4,150.5 DRIVE.PP 25.4,149.23 25.4,147.96 DRIVE.SS 25.4,146.69 25.4,145.42 DRIVE.UU 26.04,144.78 27.3,144.78 DRIVE.VV 27.94,145.42 27.94,146.69 DRIVE.TT | DRIVE.NN 27.3,152.4 26.04,152.4 DRIVE.MM | DRIVE.MM 25.4,153.04 25.4,154.31 DRIVE.KK 25.4,155.58 25.4,156.85 DRIVE.HH | DRIVE.JJ 27.3,157.48 26.04,157.48 DRIVE.HH | DRIVE.HH 25.4,158.12 25.4,159.39 DRIVE.EE 25.4,160.66 25.4,161.93 DRIVE.CC | DRIVE.DD 27.3,162.56 26.04,162.56 DRIVE.CC | DRIVE.CC 25.4,163.2 25.4,164.47 DRIVE.AA 25.4,165.74 25.4,167.01 DRIVE.Y | DRIVE.Y 25.4,168.28 25.4,169.55 DRIVE.W 25.4,170.82 25.4,172.09 DRIVE.U | DRIVE.V 27.3,172.72 26.04,172.72 DRIVE.U | DRIVE.U 25.4,173.36 25.4,174.63 DRIVE.S 25.4,175.9 25.4,177.17 DRIVE.P
  Top 0.762: DRIVE.R 27.3,177.8 26.04,177.8 DRIVE.P | DRIVE.P 25.4,178.44 25.4,179.71 DRIVE.M 25.4,180.98 25.4,182.25 DRIVE.K | DRIVE.K 25.4,183.52 25.4,184.79 DRIVE.H 25.4,186.06 25.4,187.33 DRIVE.E | DRIVE.F 27.3,187.96 26.04,187.96 DRIVE.E | DRIVE.E 25.4,188.6 25.4,189.87 DRIVE.C 25.4,191.14 25.4,192.41 DRIVE.A 26.04,193.04 27.3,193.04 DRIVE.B | DRIVE.Z 27.3,167.64 26.04,167.64 DRIVE.Y | DRIVE.L 27.3,182.88 26.04,182.88 DRIVE.K | C31.2 82.55,153.04 82.55,173.99 81.92,174.63 E32.7 81.92,175.9 83.82,177.8 83.82,193.68 82.55,194.95 C32.2 | C34.2 59.69,112.4 59.69,132.08 E35.7 59.05,132.72 60.96,134.62 60.96,150.5 59.69,151.77 C35.2 59.69,153.04 59.69,171.45 59.05,172.09 E36.8 | R17.1 43.81,154.94 45.72,156.85 48.26,156.85 48.26,155.58 R16.1 | 83.19,22.23 83.19,16.51 81.28,14.61 81.28,13.97 U$2.CT1 | 83.19,22.23 83.19,29.21 88.27,34.29 C43.- | C25.2 105.41,69.22 104.78,69.85 104.78,90.81 E26.7 104.78,92.08 106.68,93.98 106.68,109.86 105.41,111.13 C26.2 | C30.2 82.55,111.13 83.82,109.86 83.82,93.98 81.92,92.08 E30.7 81.92,90.81 82.55,90.17 82.55,69.22 C29.2 82.55,67.95 83.82,66.68 83.82,50.8 81.92,48.9 X29.7 80.64,47.63 80.64,30.48 | 83.19,22.23 80.64,22.23 80.64,30.48 | E41.8 13.34,88.27 13.34,69.85 13.97,69.22 C40.2 13.97,67.95 15.24,66.68 15.24,43.18 | 15.24,43.18 19.68,38.74 19.68,36.83 C42.- 19.68,34.29 19.68,29.85 12.06,22.23 12.06,14.61 11.43,13.97 U$2.DT1 | 15.24,43.18 13.34,45.09 E40.8 | v124.46,17.78 125.09,18.42 125.09,43.18 126.36,44.45 126.36,45.09 E21.8 | 80.64,30.48 59.05,30.48 59.05,45.09 E33.8
  Bottom 0.762: v117.47,135.26 120.65,132.08 125.73,132.08 E23.7 | U$2.AT2 212.72,13.97 v212.72,15.24 225.43,15.24 | 225.43,15.24 254,15.24 254,13.97 U$2.AC2 | U$2.BC2 186.06,13.97 186.06,34.93 194.31,34.93 200.03,40.64 v219.71,40.64 224.16,36.2 224.79,36.2 C45.- 225.43,34.29 225.43,15.24 | v219.07,114.94 238.76,114.94 241.94,111.76 C2.2 | E2.7 240.03,91.44 228.6,91.44 226.69,89.54 221.62,89.54 219.71,91.44 E6.7 217.17,91.44 215.26,89.54 199.39,89.54 197.49,91.44 196.85,91.44 E10.7 194.31,91.44 192.41,89.54 169.54,89.54 | 192.41,43.82 191.13,42.55 182.88,42.55 176.53,36.2 C44.- | 192.41,43.82 194.31,45.72 E9.8 | 169.54,89.54 171.45,91.44 X14.7 | 169.54,89.54 153.03,89.54 151.13,91.44 E18X.7 | 192.41,43.82 203.84,43.82 204.47,44.45 238.76,44.45 240.03,45.72 E1.8 | C21.2 128.91,68.58 130.81,66.68 146.69,66.68 148.59,68.58 150.5,68.58 C17.2 | 236.22,172.72 240.03,172.72 E4.8 | 236.22,172.72 222.25,172.72 219.71,175.26 E8.7 | 236.22,172.72 240.66,177.17 E4.6 | C4.2 241.94,195.58 240.03,193.68 222.25,193.68 220.34,195.58 C8.2 219.07,195.58 217.17,193.68 199.39,193.68 197.49,195.58 C12.2 | E11.10 201.93,137.16 196.85,137.16 E11.5 | 130.18,173.36 146.69,173.36 148.59,175.26 E20.7 151.13,175.26 153.03,173.36 169.54,173.36 | 130.18,173.36 128.27,175.26 E24.7 | 130.18,173.36 107.31,173.36 105.41,175.26 E28.7 | C19.2 156.84,152.4 173.35,152.4 C15.2 | 169.54,173.36 171.45,175.26 E16.7 | 169.54,173.36 192.41,173.36 194.31,175.26 E12.7 | C41.2 14.61,111.76 34.29,131.45 34.92,131.45 E39.7 | E34.7 57.15,91.44 55.24,89.54 38.73,89.54 36.83,91.44 E38.7 | R14.1 34.92,180.34 32.38,182.88 28.57,182.88 DRIVE.L
  Bottom 0.762: R17.1 42.55,154.94 40.01,152.4 37.47,152.4 C39.2 | R11.1 34.92,167.64 28.57,167.64 DRIVE.Z | E39.1 34.29,147.32 28.57,147.32 DRIVE.TT | 80.01,193.68 62.23,193.68 60.33,195.58 C36.2 | 80.01,193.68 81.92,195.58 C32.2 | C31.2 81.92,152.4 81.28,153.04 73.66,153.04 71.75,154.94 R12.1 70.48,154.94 68.58,153.04 67.31,153.04 66.04,154.31 R10.1 65.41,154.94 62.87,154.94 60.33,152.4 C35.2 59.05,152.4 51.44,152.4 48.9,154.94 R16.1 | C26.2 104.78,111.76 102.87,109.86 85.09,109.86 83.19,111.76 C30.2 | E21.8 125.73,45.72 114.3,45.72 112.39,43.82 107.31,43.82 105.41,45.72 E25.8 102.87,45.72 100.97,43.82 55.24,43.82 | 29.84,43.82 22.23,36.2 21.59,36.2 C42.- 19.05,34.93 9.53,34.93 9.53,19.69 10.16,19.05 50.8,19.05 50.8,13.97 U$2.DC2 | 29.84,43.82 34.29,48.26 X37.7 | 55.24,43.82 57.15,45.72 E33.8 | 29.84,43.82 55.24,43.82 | v124.46,17.78 122.56,17.78 122.56,13.97 U$2.CC2 | 80.01,193.68 87.63,193.68 88.27,194.31 103.5,194.31 104.78,195.58 C28.2 | E7.7 217.17,132.08 205.74,132.08 203.84,130.18 202.56,130.18 200.66,132.08 196.85,132.08 E11.7
INIT  (via drill 0.61)
  Top 0.254: v229.24,180.34 v229.24,133.35 229.24,97.79 224.79,97.79 224.16,98.43 224.16,99.7 225.43,100.97 E6.12 | E23.6 126.36,135.26 125.09,136.53 125.09,140.34 126.36,141.61 E23.3 126.36,142.88 125.09,144.15 125.09,187.33 | v86.36,184.15 92.08,184.15 104.78,196.85 129.54,196.85 129.54,194.95 126.36,191.77 125.09,191.77 125.09,187.33 | 125.09,187.33 126.36,186.06 E24.3 | v68.58,59.69 74.3,65.41 74.3,141.61 73.66,142.24 73.66,153.04 74.93,154.31 74.93,179.07 80.64,184.79 E32.3 | X37.12 42.55,59.06 42.55,60.33 X37.13
  Bottom 0.254: v229.24,180.34 227.97,181.61 220.98,181.61 219.71,180.34 E8.5 | E23.6 128.27,134.62 129.54,135.89 135.89,135.89 137.16,134.62 148.59,134.62 E19.6 151.13,134.62 152.4,133.35 158.75,133.35 161.29,130.81 176.53,130.81 179.07,133.35 v229.24,133.35 | v86.36,184.15 83.82,184.15 82.55,185.42 E32.3 | v68.58,59.69 45.72,59.69 44.45,58.42 X37.12
INIT\
  Top 0.254: E2.13 248.28,104.78 245.75,107.32 245.75,186.06 241.94,189.87 E4.1 | E9.1 195.58,64.14 195.58,88.27 189.23,94.62 189.23,139.07 189.87,139.7 189.87,170.82 180.97,179.71 E16.10
  Bottom 0.254: 124.46,64.77 60.96,64.77 59.69,63.5 E33.1 | 124.46,64.77 125.73,63.5 E21.1 | 124.46,64.77 183.51,64.77 184.15,64.14 193.68,64.14 194.31,63.5 E9.1 | E2.1 242.57,106.68 245.11,104.14 247.65,104.14 E2.13 | 215.9,179.07 217.17,177.8 E8.6 | 215.9,179.07 182.88,179.07 181.61,180.34 E16.10 | 215.9,179.07 243.21,179.07 243.21,188.6 241.94,189.87 E4.1
INIT_IOT\  (via drill 0.61)
  Top 0.254: v219.71,87.63 222.25,90.17 222.25,128.27 220.34,130.18 220.34,137.8 219.71,138.43 216.53,138.43 216.53,140.34 217.17,140.97 220.34,140.97 220.34,142.88 219.07,144.15 E7.2
  Bottom 0.254: v219.71,87.63 22.86,87.63 21.59,88.9 E41.9
INITIALIZE  (via drill 0.61)
  Top 0.254: v193.68,124.46 193.68,132.72 194.94,133.99 E11.6 | v99.06,119.38 94.61,114.94 94.61,27.94 87.63,20.96 87.63,13.97 U$2.CR1
  Bottom 0.254: v193.68,124.46 188.59,119.38 v99.06,119.38
INT_RQST\  (via drill 0.61)
  Top 0.254: v138.43,34.93 138.43,82.55 149.22,93.35 E18X.6 | v104.78,27.94 90.81,13.97 U$2.CP1
  Bottom 0.254: v138.43,34.93 131.44,27.94 v104.78,27.94
INTERNAL_IO\  (via drill 0.61)
  Top 0.254: v152.4,86.36 152.4,99.06 150.5,100.97 E18X.3 | v116.2,83.82 107.31,74.93 107.31,20.96 100.33,13.97 U$2.CL1
  Bottom 0.254: v152.4,86.36 149.86,83.82 v116.2,83.82
INTR_IOT\  (via drill 0.61)
  Top 0.254: v208.91,82.55 216.53,90.17 216.53,92.08 217.81,93.35 E6.6
  Bottom 0.254: v208.91,82.55 22.86,82.55 13.97,91.44 E41.7
IO_PAUSE\  (via drill 0.61)
  Top 0.254: v109.86,120.65 117.47,113.03 117.47,13.97 U$2.CD1
  Bottom 0.254: v109.86,120.65 50.8,120.65 36.83,134.62 E39.6
LCD_IOT  (via drill 0.61)
  Top 0.254: v45.72,100.33 54.61,109.22 v54.61,146.05 | v100.33,150.5 102.23,152.4 v102.23,172.09 102.23,180.98 103.5,182.25 E28.4 | v202.56,172.09 205.1,174.63 205.1,178.44 203.84,179.71 E12.10
  Bottom 0.254: v45.72,100.33 38.1,100.33 36.83,99.06 E38.4 | v54.61,146.05 59.05,150.5 v100.33,150.5 | v102.23,172.09 v202.56,172.09
LCD_IOT\  (via drill 0.61)
  Top 0.254: v192.41,102.87 189.87,105.41 189.87,106.05 190.5,106.68 190.5,177.8 194.94,182.25 E12.4
  Bottom 0.254: E41.2 13.97,104.14 15.24,102.87 33.02,102.87 34.29,101.6 E38.3 36.83,101.6 38.1,102.87 v192.41,102.87 204.47,102.87 205.1,102.24 216.53,102.24 217.17,101.6 E6.3 | E16.5 173.99,180.34 175.26,181.61 193.04,181.61 194.31,182.88 E12.4
MAINT  (via drill 0.61)
  Top 0.254: v163.19,167.01 163.19,172.09 158.12,177.17 E20.9 | v247.65,158.75 250.82,155.58 250.82,95.89 249.56,94.62 E2.9
  Bottom 0.254: v163.19,167.01 171.45,158.75 v247.65,158.75
MAINT\  (via drill 0.61)
  Top 0.254: v100.33,99.06 100.33,149.23 99.06,150.5 99.06,185.42 103.5,189.87 E28.1 | v185.42,95.25 184.78,95.89 184.78,125.1 177.8,132.08 177.8,182.88 179.71,184.79 E16.12
  Bottom 0.254: 205.1,100.33 209.55,100.33 217.17,92.71 246.38,92.71 247.65,91.44 E2.8 | 205.1,100.33 198.12,100.33 196.85,101.6 E10.3 | 100.33,97.79 101.6,97.79 102.87,99.06 E26.4 105.41,99.06 106.05,99.06 107.31,97.79 113.03,97.79 113.67,98.43 125.09,98.43 125.73,99.06 E22.4 | 100.33,97.79 83.82,97.79 82.55,99.06 E30.4 | E32.11 90.17,182.88 90.81,182.25 100.97,182.25 102.87,184.15 109.22,184.15 109.86,184.79 110.49,185.42 E28.12 113.03,185.42 114.3,186.69 115.57,186.69 | 115.57,186.69 177.8,186.69 179.07,185.42 E16.12 | v100.33,99.06 100.33,97.79 | 205.1,100.33 205.1,95.25 v185.42,95.25 | 115.57,186.69 113.03,189.23 106.68,189.23 105.41,190.5 E28.1
MD03\  (via drill 0.61)
  Top 0.254: v56.52,80.01 55.88,80.65 55.88,137.16 57.78,139.07 E35.4 | v219.71,76.84 220.98,75.57 220.98,15.24 222.25,13.97 U$2.AP1
  Bottom 0.254: v56.52,80.01 59.69,76.84 v219.71,76.84
MD04\  (via drill 0.61)
  Top 0.254: v162.56,125.1 163.19,124.46 163.19,15.88 165.1,13.97 U$2.BK1
  Bottom 0.254: v162.56,125.1 56.52,125.1 56.52,132.72 57.78,133.99 E35.6
MD05\  (via drill 0.61)
  Top 0.254: v58.42,129.54 56.52,131.45 56.52,135.26 57.78,136.53 E35.5 | v161.29,126.37 161.29,39.37 161.93,38.74 161.93,13.97 U$2.BL1
  Bottom 0.254: v58.42,129.54 61.59,126.37 v161.29,126.37
MD06\  (via drill 0.61)
  Top 0.254: E31.4 80.64,139.07 78.11,136.53 78.11,67.95 v77.47,67.31 76.83,66.68 76.83,39.37 v76.2,38.74 | v150.5,25.4 150.5,22.23 158.75,13.97 U$2.BM1
  Bottom 0.254: v77.47,67.31 17.78,67.31 13.97,63.5 E40.1 | v150.5,25.4 139.7,36.2 116.84,36.2 113.67,33.02 81.92,33.02 v76.2,38.74
MD07\  (via drill 0.61)
  Top 0.254: E31.5 81.92,137.8 83.19,139.07 83.19,140.97 80.01,140.97 77.47,138.43 77.47,82.55 v76.2,81.28 76.2,40.01 v74.93,38.74 | v149.22,24.13 149.22,17.15 152.4,13.97 U$2.BP1
  Bottom 0.254: v76.2,81.28 10.79,81.28 10.79,60.33 12.06,59.06 E40.3 | v149.22,24.13 146.69,26.67 97.16,26.67 91.44,32.39 81.28,32.39 v74.93,38.74
MD08\  (via drill 0.61)
  Top 0.254: v29.84,52.07 31.75,50.17 31.75,13.97 U$2.DK1
  Bottom 0.254: v29.84,52.07 15.24,52.07 13.97,53.34 E40.5 12.06,53.98 8.89,53.98 8.89,110.49 34.29,135.89 59.69,135.89 62.23,133.35 78.74,133.35 80.01,134.62 E31.6
MD09\  (via drill 0.61)
  Top 0.254: v26.04,59.69 28.57,57.15 28.57,13.97 U$2.DL1
  Bottom 0.254: v26.04,59.69 22.86,59.69 21.59,60.96 E40.15
MD10\  (via drill 0.61)
  Top 0.254: v26.04,54.61 26.04,13.97 U$2.DM1
  Bottom 0.254: v26.04,54.61 22.86,54.61 21.59,55.88 E40.13
MD11\  (via drill 0.61)
  Top 0.254: v24.13,50.8 23.5,50.17 23.5,16.51 20.95,13.97 U$2.DP1
  Bottom 0.254: v24.13,50.8 21.59,50.8 E40.11
MSB8  (via drill 0.61)
  Top 0.254: v231.78,90.17 231.78,92.71 242.57,92.71 243.84,93.98 243.84,134.62 241.94,136.53 E3.5 | v194.31,78.11 193.68,77.47 v193.68,67.31 193.68,57.79 194.94,56.52 E9.4 | v146.69,50.8 146.69,66.04 147.96,67.31 149.22,67.31 | 149.22,67.31 149.22,64.14 X17.1 | v149.86,67.31 149.22,67.31
  Bottom 0.254: v231.78,90.17 219.71,78.11 v194.31,78.11 | v146.69,50.8 135.89,50.8 E21.11 | v193.68,67.31 v149.86,67.31
MSB12  (via drill 0.61)
  Top 0.254: v214,50.8 214.63,51.44 214.63,66.04 215.9,67.31 216.53,67.31 216.53,66.68 217.81,65.41 217.81,64.14 X5.1 | v237.49,140.97 230.5,133.99 230.5,76.2 222.25,67.95 v222.25,63.5
  Bottom 0.254: v214,50.8 204.47,50.8 E9.11 | v237.49,140.97 240.66,144.15 E3.2 | v222.25,63.5 219.71,63.5 X5.1
N$1
  Bottom 0.254: E35.10 67.31,137.16 68.58,135.89 86.36,135.89 87.63,134.62 E31.11 89.53,135.26 90.81,135.26 90.81,140.34 89.53,141.61 E31.14
N$2  (via drill 0.61)
  Top 0.254: v193.68,52.07 193.68,50.17 194.94,48.9 E9.7
  Bottom 0.254: v193.68,52.07 223.52,52.07 224.79,50.8 X5.9
N$3  (via drill 0.61)
  Top 0.254: v167,149.86 167,182.25 172.09,187.33 E16.2 | X29.10 88.27,53.98 87,55.25 87,56.52 87.63,57.15 90.81,57.15 90.81,59.06 89.53,60.33 X29.13 89.53,61.6 90.81,62.87 v90.81,74.3 | X17.10 156.84,53.98 155.57,55.25 155.57,59.06 156.84,60.33 X17.13 156.84,61.6 153.67,64.77 v153.67,74.3 153.67,134.62 155.57,136.53 155.57,142.88 156.84,144.15 E19.13
  Bottom 0.254: v167,149.86 161.93,144.78 158.75,144.78 E19.13 | X29.5 82.55,53.34 87.63,53.34 X29.10 | X29.2 82.55,60.96 87.63,60.96 X29.13 | X17.5 151.13,53.34 156.21,53.34 X17.10 | X17.2 151.13,60.96 156.21,60.96 X17.13 | v153.67,74.3 v90.81,74.3
N$4
  Top 0.254: E19.11 158.12,140.34 159.38,141.61 159.38,173.36 158.12,174.63 E20.8
N$5
  Top 0.254: E31.15 89.53,144.15 90.81,142.88 90.81,139.07 89.53,137.8 E31.12
  Bottom 0.254: E35.11 67.31,139.7 68.58,138.43 86.36,138.43 87.63,137.16 E31.12
N$6
  Bottom 0.254: 82.55,140.97 86.36,140.97 87.63,139.7 E31.13 | 82.55,140.97 68.58,140.97 67.31,142.24 E35.12 | 82.55,140.97 88.27,146.69 E31.16
N$7  (via drill 0.61)
  Top 0.254: v70.48,54.61 74.93,59.06 v74.93,142.24
  Bottom 0.254: v70.48,54.61 57.15,54.61 52.07,49.53 15.24,49.53 13.97,50.8 E40.6 | v74.93,142.24 80.01,142.24 E31.3
N$8  (via drill 0.61)
  Top 0.254: v66.04,109.86 72.39,116.21 v72.39,144.78
  Bottom 0.254: v66.04,109.86 9.53,109.86 9.53,57.79 11.43,55.88 E40.4 | v72.39,144.78 80.01,144.78 E31.2
N$9  (via drill 0.61)
  Top 0.254: v10.79,144.78 10.79,62.87 12.06,61.6 E40.2
  Bottom 0.254: v10.79,144.78 12.06,146.05 39.37,146.05 41.91,143.51 54.61,143.51 57.15,146.05 78.74,146.05 80.01,147.32 E31.1
N$10
  Bottom 0.254: 29.21,143.51 33.02,143.51 34.29,144.78 E39.2 | 29.21,143.51 8.26,143.51 8.26,52.71 12.06,48.9 E40.7 | 29.21,143.51 34.29,138.43 60.96,138.43 64.77,134.62 E35.9
N$11  (via drill 0.61)
  Top 0.254: v33.66,140.97 33.66,108.59 34.92,107.32 E38.1 | v75.56,143.51 75.56,174.63 80.64,179.71 E32.5 | 151.13,105.41 150.5,104.78 E18X.2 | 151.13,105.41 152.4,106.68 v152.4,113.03 | 151.13,105.41 150.5,106.05 E18X.1
  Bottom 0.254: v33.66,140.97 55.88,140.97 57.15,142.24 E35.3 59.69,142.24 60.96,143.51 v75.56,143.51 | v152.4,113.03 108.58,113.03 104.14,108.59 38.73,108.59 36.83,106.68 E38.1
N$12  (via drill 0.61)
  Top 0.254: v177.16,81.28 177.16,98.43 175.26,100.33 175.26,106.68 170.81,111.13 170.81,142.24 168.91,144.15 168.91,181.61 172.09,184.79 E16.3 | v208.91,79.38 217.17,71.12 217.17,67.31 220.34,64.14 220.34,62.87 | 220.34,62.87 219.07,61.6 X5.2 | 220.34,62.87 220.34,55.25 219.07,53.98 X5.5
  Bottom 0.254: X5.5 219.71,53.34 224.79,53.34 X5.10 | X5.2 219.71,60.96 224.79,60.96 X5.13 | v177.16,81.28 179.07,79.38 v208.91,79.38
N$13
  Top 0.254: E13.1 171.45,63.5 170.81,63.5 PAD10.1
N$14
  Top 0.254: E13.2 171.45,60.96 170.81,60.96 PAD11.1
N$15
  Top 0.254: E13.3 171.45,58.42 170.81,58.42 PAD12.1
N$16
  Top 0.254: E13.4 171.45,55.88 170.81,55.88 PAD13.1
N$17
  Top 0.254: E13.5 171.45,53.34 170.81,53.34 PAD14.1
N$18
  Top 0.254: E13.6 171.45,50.8 170.81,50.8 PAD15.1
N$19
  Top 0.254: E13.7 171.45,48.26 170.81,48.26 PAD16.1
N$20
  Top 0.254: E13.8 171.45,45.72 170.81,45.72 PAD17.1
N$21
  Bottom 0.254: E12.3 196.85,185.42 197.49,184.79 201.29,184.79 201.93,184.15 236.22,184.15 240.03,180.34 E4.5
N$22  (via drill 0.61)
  Top 0.254: v191.77,177.8 191.13,177.17 v191.13,105.41 | X14.1 172.09,106.05 172.09,104.78 X14.2
  Bottom 0.254: v191.77,177.8 194.31,177.8 E12.6 | v191.13,105.41 175.26,105.41 X14.2
N$23
  Top 0.254: E13.16 181.61,63.5 182.25,63.5 PAD20.1
N$24
  Top 0.254: E13.15 181.61,60.96 182.25,60.96 PAD21.1
N$25
  Top 0.254: E13.14 181.61,58.42 182.25,58.42 PAD22.1
N$26
  Top 0.254: E13.13 181.61,55.88 182.25,55.88 PAD23.1
N$27
  Top 0.254: E13.12 181.61,53.34 182.25,53.34 PAD24.1
N$28
  Top 0.254: E13.11 181.61,50.8 182.25,50.8 PAD25.1
N$29
  Top 0.254: E13.10 181.61,48.26 182.25,48.26 PAD26.1
N$30
  Top 0.254: E13.9 181.61,45.72 182.25,45.72 PAD27.1
N$31  (via drill 0.61)
  Top 0.254: v67.94,57.15 67.94,52.71 66.67,51.44 E33.11 | v124.46,63.5 124.46,62.23 128.27,62.23 128.91,61.6 128.91,57.79 127.64,56.52 E21.4
  Bottom 0.254: v67.94,57.15 71.75,60.96 78.74,60.96 80.01,62.23 | 80.01,62.23 80.64,62.87 X29.1 | v124.46,63.5 123.83,62.87 113.67,62.87 113.03,62.23 80.01,62.23
N$32  (via drill 0.61)
  Top 0.254: v205.1,116.21 205.1,103.51 203.84,102.24 E10.12 | v192.41,125.73 192.41,177.17 194.94,179.71 E12.5
  Bottom 0.254: v205.1,116.21 195.58,125.73 v192.41,125.73
N$33  (via drill 0.61)
  Top 0.254: v210.19,53.34 210.19,52.71 203.84,46.36 E9.9
  Bottom 0.254: v210.19,53.34 210.82,53.98 215.26,53.98 217.17,55.88 X5.4
N$34  (via drill 0.61)
  Top 0.254: E10.2 194.94,103.51 v193.04,101.6 193.04,96.52 194.94,94.62 E10.6
  Bottom 0.254: X14.12 v193.04,101.6
N$35
  Bottom 0.254: E12.1 194.94,189.87 193.68,188.6 193.68,184.15 200.66,184.15 201.93,182.88 E12.11
N$36
  Top 0.254: E12.8 202.56,175.9 199.39,179.07 199.39,194.95 197.49,196.85 193.68,196.85 193.68,189.87 194.94,188.6 E12.2
N$37
  Top 0.254: E8.2 217.81,188.6 216.53,189.87 216.53,194.31 219.07,196.85 238.76,196.85 238.76,152.4 243.21,147.96 243.21,144.15 241.94,142.88 E3.3
  Bottom 0.254: E3.3 242.57,142.24 245.11,144.78 247.65,144.78 E3.13
N$38
  Top 0.254: E3.11 248.28,140.34 248.28,141.61 E3.12
N$39
  Bottom 0.254: E3.6 242.57,134.62 247.65,134.62 E3.9
N$40  (via drill 0.61)
  Top 0.254: v160.02,181.61 164.47,177.17 v164.47,128.91
  Bottom 0.254: v160.02,181.61 137.16,181.61 135.89,182.88 E24.11 | v164.47,128.91 165.74,127.64 220.34,127.64 222.88,130.18 249.56,130.18 250.82,131.45 250.82,136.53 249.56,136.53 E3.10
N$42  (via drill 0.61)
  Top 0.254: E27.4 104.78,140.34 111.12,146.69 E27.16 | v168.28,137.16 v168.28,128.91 168.28,100.97 172.09,97.16 X14.5
  Bottom 0.254: v168.28,137.16 167,138.43 106.68,138.43 105.41,139.7 E27.4 | v168.28,128.91 203.84,128.91 205.74,130.81 246.38,130.81 247.65,132.08 E3.8
N$43
  Top 0.254: E8.9 225.43,177.17 220.98,172.72 220.98,140.34 220.34,139.7 219.71,139.7 E7.4
  Bottom 0.254: E11.3 196.85,142.24 198.12,140.97 215.9,140.97 217.17,139.7 E7.4
N$44  (via drill 0.61)
  Top 0.254: v222.25,182.88 224.16,184.79 224.16,186.06 225.43,187.33 E8.13
  Bottom 0.254: v222.25,182.88 219.71,182.88 E8.4 | E4.2 240.03,187.96 238.76,189.23 228.6,189.23 227.33,187.96 E8.13
N$45  (via drill 0.61)
  Top 0.254: v142.88,189.23 150.5,196.85 165.74,196.85 v165.74,134.62
  Bottom 0.254: v142.88,189.23 129.54,189.23 128.27,187.96 E24.2 | v165.74,134.62 166.37,135.26 170.81,135.26 171.45,135.89 215.9,135.89 217.17,137.16 E7.5
N$46  (via drill 0.61)
  Top 0.254: v109.86,108.59 106.68,111.76 106.68,124.46 102.23,128.91 102.23,140.34 103.5,141.61 E27.3
  Bottom 0.254: v109.86,108.59 128.27,108.59 129.54,109.86 147.96,109.86 149.22,108.59 189.23,108.59 192.41,105.41 223.52,105.41 224.79,104.14 E6.13
N$47  (via drill 0.61)
  Top 0.254: v144.78,161.29 132.08,173.99 132.08,193.04 130.81,193.04 128.27,190.5 E24.1 | v193.68,157.48 193.68,146.69 194.94,145.42 E11.2
  Bottom 0.254: v144.78,161.29 148.59,157.48 v193.68,157.48
N$48
  Bottom 0.254: E6.1 219.71,106.68 220.34,106.05 224.16,106.05 224.79,105.41 236.22,105.41 240.03,101.6 E2.3 242.57,101.6 245.11,101.6 247.65,99.06 E2.11
N$49
  Bottom 0.254: E19.5 151.13,137.16 156.21,137.16 E19.10
N$50  (via drill 0.61)
  Top 0.254: E40.9 20.95,46.36 22.23,47.63 22.23,94.62 20.95,95.89 E41.12 19.68,97.16 18.41,98.43 18.41,102.87 21.59,102.87 v22.86,104.14
  Bottom 0.254: v22.86,104.14 34.29,104.14 E38.2
N$51
  Bottom 0.254: E40.14 19.05,58.42 17.78,57.15 11.43,57.15 10.16,58.42 10.16,97.79 17.78,97.79 19.05,99.06 E41.13
N$52  (via drill 0.61)
  Top 0.254: v24.13,53.34 24.77,53.98 24.77,97.16 20.95,100.97 E41.14
  Bottom 0.254: v24.13,53.34 21.59,53.34 E40.12
N$53
  Top 0.254: E40.10 19.68,48.9 17.78,50.8 17.78,103.51 18.41,104.14 19.05,104.14 E41.15
N$54  (via drill 0.61)
  Top 0.254: v147.96,108.59 147.96,137.8 149.22,139.07 E19.4
  Bottom 0.254: v147.96,108.59 133.99,108.59 132.08,106.68 128.27,106.68 E22.1
N$55  (via drill 0.61)
  Top 0.254: v130.81,107.95 130.81,135.89 127.64,139.07 E23.4
  Bottom 0.254: v130.81,107.95 110.49,107.95 109.22,106.68 105.41,106.68 E26.1
N$56
  Bottom 0.254: E23.5 128.27,137.16 133.35,137.16 E23.10
N$57
  Bottom 0.254: E23.2 128.27,144.78 133.35,144.78 E23.13
N$58  (via drill 0.61)
  Top 0.254: v85.72,142.24 85.72,131.45 81.28,127 81.28,107.32 E30.1
  Bottom 0.254: v85.72,142.24 87,143.51 100.33,143.51 102.87,146.05 124.46,146.05 125.73,147.32 E23.1
N$59  (via drill 0.61)
  Top 0.254: v85.09,96.52 87,98.43 87,99.7 88.27,100.97 E30.12
  Bottom 0.254: v85.09,96.52 82.55,96.52 E30.5
N$60
  Bottom 0.254: E9.5 196.85,53.34 198.12,54.61 214.63,54.61 217.17,57.15 223.52,57.15 224.79,58.42 X5.12
N$61  (via drill 0.61)
  Top 0.254: v109.86,95.25 109.86,99.7 111.12,100.97 E26.12
  Bottom 0.254: v109.86,95.25 106.68,95.25 105.41,96.52 E26.5
N$62  (via drill 0.61)
  Top 0.254: v140.97,45.72 142.88,47.63 v142.88,55.88
  Bottom 0.254: v140.97,45.72 135.89,45.72 E21.9 | v142.88,55.88 148.59,55.88 X17.4
N$63  (via drill 0.61)
  Top 0.254: v132.08,44.45 128.27,48.26 E21.7 | v149.22,44.45 154.31,49.53 v154.31,50.8
  Bottom 0.254: v132.08,44.45 v149.22,44.45 | v154.31,50.8 156.21,50.8 X17.9
N$64  (via drill 0.61)
  Top 0.254: v131.44,57.79 127.64,53.98 E21.5
  Bottom 0.254: v131.44,57.79 133.35,59.69 153.67,59.69 154.94,58.42 156.21,58.42 X17.12
N$65  (via drill 0.61)
  Top 0.254: v62.23,53.34 v62.23,69.85 | v83.82,69.85 86.36,67.31 86.36,60.96 88.27,59.06 X29.12
  Bottom 0.254: v62.23,53.34 59.69,53.34 E33.5 | v62.23,69.85 v83.82,69.85
N$66
  Top 0.254: E33.9 66.67,45.09 74.3,37.47 79.38,37.47 79.38,53.98 80.64,55.25 X29.4
N$67  (via drill 0.61)
  Top 0.254: v86.36,46.99 87,47.63 87,48.9 88.27,50.17 X29.9
  Bottom 0.254: v86.36,46.99 80.01,46.99 79.38,47.63 74.93,47.63 74.3,46.99 60.96,46.99 59.69,48.26 E33.7
N$68  (via drill 0.61)
  Top 0.254: v130.81,96.52 132.72,98.43 132.72,99.7 133.99,100.97 E22.12
  Bottom 0.254: v130.81,96.52 128.27,96.52 E22.5
N$69  (via drill 0.61)
  Top 0.254: v73.03,93.98 73.03,97.16 66.67,103.51 E34.13
  Bottom 0.254: v73.03,93.98 76.83,90.17 129.54,90.17 133.35,93.98 E22.9 135.89,93.98 140.97,99.06 148.59,99.06 E18X.4
N$70  (via drill 0.61)
  Top 0.254: v107.95,107.95 108.58,107.32 108.58,95.25 109.86,93.98 110.49,93.98 E26.9
  Bottom 0.254: v107.95,107.95 60.96,107.95 59.69,106.68 E34.1
N$71  (via drill 0.61)
  Top 0.254: v205.1,143.51 215.26,133.35 v215.26,100.97
  Bottom 0.254: v205.1,143.51 175.26,143.51 173.99,142.24 E15.3 | v215.26,100.97 217.17,99.06 E6.4
N$72
  Bottom 0.254: E34.10 67.31,96.52 68.58,95.25 82.55,95.25 83.82,93.98 87.63,93.98 E30.9
N$73  (via drill 0.61)
  Top 0.254: v53.98,104.14 53.98,102.24 43.81,92.08 E38.8
  Bottom 0.254: v53.98,104.14 57.15,104.14 E34.2
N$74
  Bottom 0.254: E38.10 44.45,96.52 45.09,97.16 56.52,97.16 57.15,97.79 60.96,97.79 64.77,101.6 E34.12
N$75  (via drill 0.61)
  Top 0.254: v46.35,95.89 46.35,98.43 43.81,100.97 E38.12
  Bottom 0.254: v46.35,95.89 46.99,95.25 63.5,95.25 64.77,93.98 E34.9
N$76  (via drill 0.61)
  Top 0.254: v146.69,135.89 146.69,99.7 149.22,97.16 E18X.5
  Bottom 0.254: v146.69,135.89 170.18,135.89 171.45,137.16 E15.5
N$77
  Top 0.254: E18X.9 156.84,94.62 156.84,95.89 E18X.10
  Bottom 0.254: E10.8 201.93,91.44 200.66,92.71 160.02,92.71 158.75,93.98 E18X.9
N$78
  Bottom 0.254: E28.6 105.41,177.8 106.68,179.07 124.46,179.07 125.73,180.34 E24.5
N$79  (via drill 0.61)
  Top 0.254: v147.96,176.53 147.96,186.06 149.22,187.33 E20.2
  Bottom 0.254: v147.96,176.53 170.18,176.53 171.45,177.8 E16.6
N$80  (via drill 0.61)
  Top 0.254: v116.2,182.88 116.2,179.71 112.39,175.9 E28.8
  Bottom 0.254: v116.2,182.88 125.73,182.88 E24.4
N$81  (via drill 0.61)
  Top 0.254: v106.05,165.1 v115.57,174.63
  Bottom 0.254: v106.05,165.1 98.42,165.1 84.45,151.13 50.8,151.13 44.45,144.78 E39.13 | v115.57,174.63 117.47,176.53 132.08,176.53 133.35,177.8 E24.9 135.89,177.8 137.16,179.07 177.8,179.07 179.07,177.8 E16.9
N$82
